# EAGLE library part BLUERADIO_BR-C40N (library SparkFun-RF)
Bluetooth SMD Module BR-C40A with antenna cut off. 50 Ohm antenna trace and connector required. Footprint fully proven. Spark Fun Electronics SKU : WRL-00149

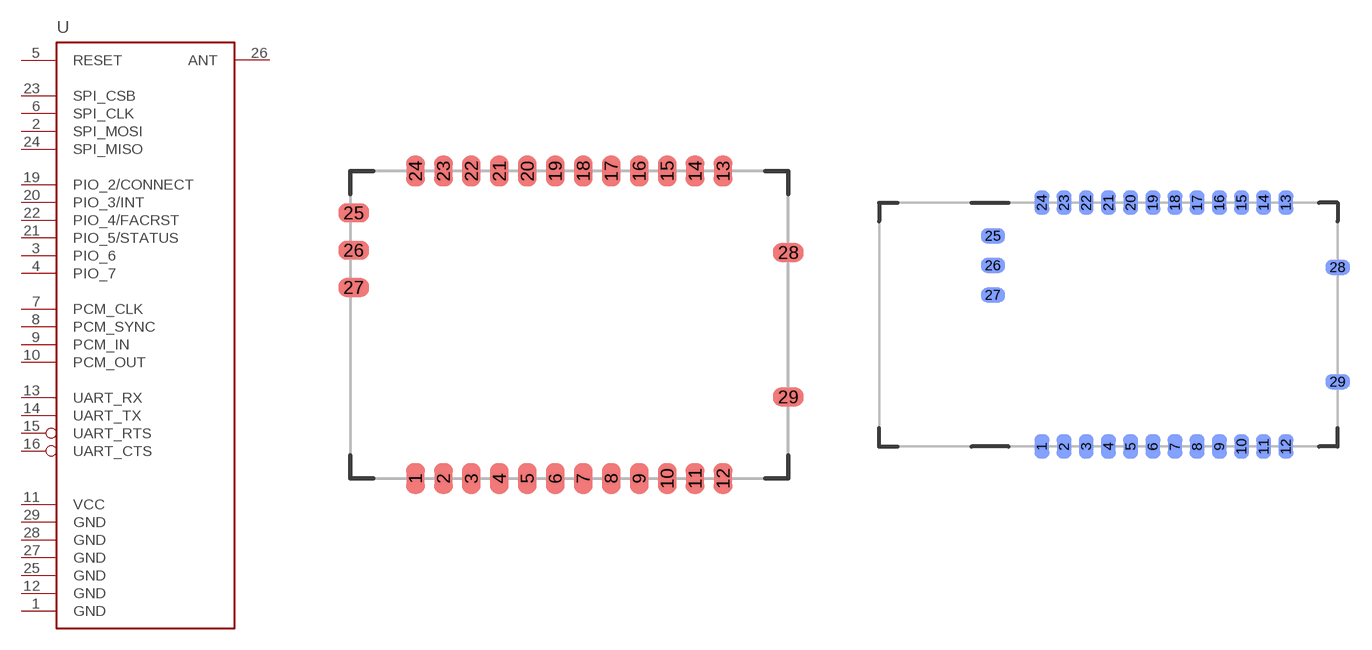
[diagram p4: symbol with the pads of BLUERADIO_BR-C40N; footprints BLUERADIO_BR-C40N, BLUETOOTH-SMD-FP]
Designator prefix -

## BLUERADIO_BR-C40NBAS  [BLUERADIO_BR-C40N]
1  GND  pwr
2  SPI_MOSI
3  PIO_6
4  PIO_7
5  RESET
6  SPI_CLK
7  PCM_CLK
8  PCM_SYNC
9  PCM_IN
10  PCM_OUT
11  VCC
12  GND  pwr
13  UART_RX  in
14  UART_TX  out
15  UART_RTS  out
16  UART_CTS  in
19  PIO_2/CONNECT  out
20  PIO_3/INT  in
21  PIO_5/STATUS  out
22  PIO_4/FACRST
23  SPI_CSB
24  SPI_MISO
25  GND  pwr
26  ANT
27  GND  pwr
28  GND  pwr
29  GND  pwr

## BLUERADIO_BR-C40NSFE  [BLUETOOTH-SMD-FP]
Pads as for BLUERADIO_BR-C40N

## BLUERADIO_BR-C40NINTERNAL  [BLUETOOTH-INTERNAL-FP]
Pads as for BLUERADIO_BR-C40N

## BLUERADIO_BR-C40NINT2  [BLUETOOTH-INTERNAL-FP2]
Pads as for BLUERADIO_BR-C40N

## Footprint BLUERADIO_BR-C40N (pad centres in mm)
smd 0.8 x 1.3: 1 -6.6,-6.6; 2 -5.4,-6.6; 3 -4.2,-6.6; 4 -3,-6.6; 5 -1.8,-6.6; 6 -0.6,-6.6; 7 0.6,-6.6; 8 1.8,-6.6; 9 3,-6.6; 10 4.2,-6.6; 11 5.4,-6.6; 12 6.6,-6.6; 13 6.6,6.6; 14 5.4,6.6; 15 4.2,6.6; 16 3,6.6; 17 1.8,6.6; 18 0.6,6.6; 19 -0.6,6.6; 20 -1.8,6.6; 21 -3,6.6; 22 -4.2,6.6; 23 -5.4,6.6; 24 -6.6,6.6
smd 1.3 x 0.8: 25 -9.25,4.8; 26 -9.25,3.2; 27 -9.25,1.6; 28 9.4,3.1; 29 9.4,-3.1

## Footprint BLUETOOTH-SMD-FP (pad centres in mm)
smd 0.8 x 1.3 bottom: 1 -6.6,-6.6; 2 -5.4,-6.6; 3 -4.2,-6.6; 4 -3,-6.6; 5 -1.8,-6.6; 6 -0.6,-6.6; 7 0.6,-6.6; 8 1.8,-6.6; 9 3,-6.6; 10 4.2,-6.6; 11 5.4,-6.6; 12 6.6,-6.6; 13 6.6,6.6; 14 5.4,6.6; 15 4.2,6.6; 16 3,6.6; 17 1.8,6.6; 18 0.6,6.6; 19 -0.6,6.6; 20 -1.8,6.6; 21 -3,6.6; 22 -4.2,6.6; 23 -5.4,6.6; 24 -6.6,6.6
smd 1.3 x 0.8 bottom: 25 -9.25,4.8; 26 -9.25,3.2; 27 -9.25,1.6; 28 9.4,3.1; 29 9.4,-3.1

## Footprint BLUETOOTH-INTERNAL-FP (pad centres in mm)
smd 0.8 x 2.25 bottom: 1 -6.6,-6.6; 2 -5.4,-6.6; 3 -4.2,-6.6; 4 -3,-6.6; 5 -1.8,-6.6; 6 -0.6,-6.6; 7 0.6,-6.6; 8 1.8,-6.6; 9 3,-6.6; 10 4.2,-6.6; 11 5.4,-6.6; 12 6.6,-6.6; 13 6.6,6.6; 14 5.4,6.6; 15 4.2,6.6; 16 3,6.6; 17 1.8,6.6; 18 0.6,6.6; 19 -0.6,6.6; 20 -1.8,6.6; 21 -3,6.6; 22 -4.2,6.6; 23 -5.4,6.6; 24 -6.6,6.6
smd 1.8 x 0.8 bottom: 25 -9.25,4.8; 26 -9.25,3.2; 27 -9.25,1.6
smd 2.25 x 0.8 bottom: 28 9.4,3.1; 29 9.4,-3.1

## Footprint BLUETOOTH-INTERNAL-FP2 (pad centres in mm)
drill 0.5 pad 0.75 long: 1 -6.6,-6.6; 2 -5.4,-6.6; 3 -4.2,-6.6; 4 -3,-6.6; 5 -1.8,-6.6; 6 -0.6,-6.6; 7 0.6,-6.6; 8 1.8,-6.6; 9 3,-6.6; 10 4.2,-6.6; 11 5.4,-6.6; 12 6.6,-6.6; 13 6.6,6.6; 14 5.4,6.6; 15 4.2,6.6; 16 3,6.6; 17 1.8,6.6; 18 0.6,6.6; 19 -0.6,6.6; 20 -1.8,6.6; 21 -3,6.6; 22 -4.2,6.6; 23 -5.4,6.6; 24 -6.6,6.6; 28 9.4,3.1; 29 9.4,-3.1
smd 1.8 x 0.8 bottom: 25 -9.25,4.8; 26 -9.25,3.2; 27 -9.25,1.6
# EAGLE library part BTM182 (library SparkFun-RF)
BTM-182 Bluetooth Module from Rayson

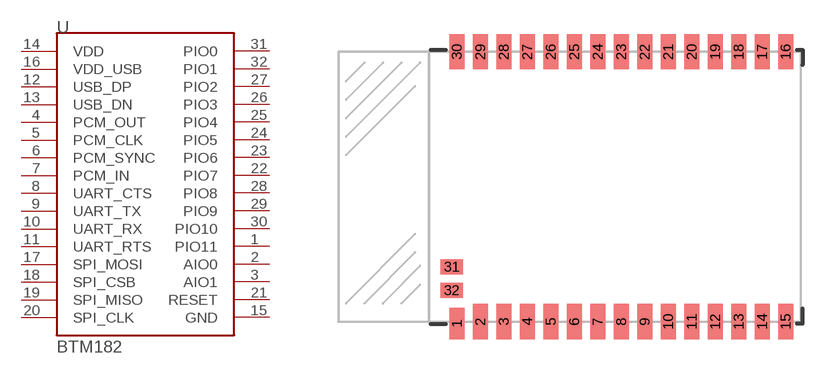
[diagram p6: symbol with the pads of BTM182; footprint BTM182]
Designator prefix U

## BTM182_  [BTM182]
1  PIO11
2  AIO0
3  AIO1
4  PCM_OUT
5  PCM_CLK
6  PCM_SYNC
7  PCM_IN
8  UART_CTS
9  UART_TX
10  UART_RX
11  UART_RTS
12  USB_DP
13  USB_DN
14  VDD
15  GND
16  VDD_USB
17  SPI_MOSI
18  SPI_CSB
19  SPI_MISO
20  SPI_CLK
21  RESET
22  PIO7
23  PIO6
24  PIO5
25  PIO4
26  PIO3
27  PIO2
28  PIO8
29  PIO9
30  PIO10
31  PIO0
32  PIO1

## Footprint BTM182 (pad centres in mm)
BTM-182 Class2 Bluetooth Module from Rayson
smd 0.8 x 1.7: 1 0,-0.1
smd 0.8 x 1.9: 2 1.27,0; 3 2.54,0; 4 3.81,0; 5 5.08,0; 6 6.35,0; 7 7.62,0; 8 8.89,0; 9 10.16,0; 10 11.43,0; 11 12.7,0; 12 13.97,0; 13 15.24,0; 14 16.51,0; 15 17.78,0; 16 17.78,14.6; 17 16.51,14.6; 18 15.24,14.6; 19 13.97,14.6; 20 12.7,14.6; 21 11.43,14.6; 22 10.16,14.6; 23 8.89,14.6; 24 7.62,14.6; 25 6.35,14.6; 26 5.08,14.6; 27 3.81,14.6; 28 2.54,14.6; 29 1.27,14.6; 30 0,14.6
smd 1.2 x 0.8: 31 -0.28,2.96; 32 -0.28,1.69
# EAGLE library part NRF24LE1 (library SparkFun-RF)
2.4GHz transceiver

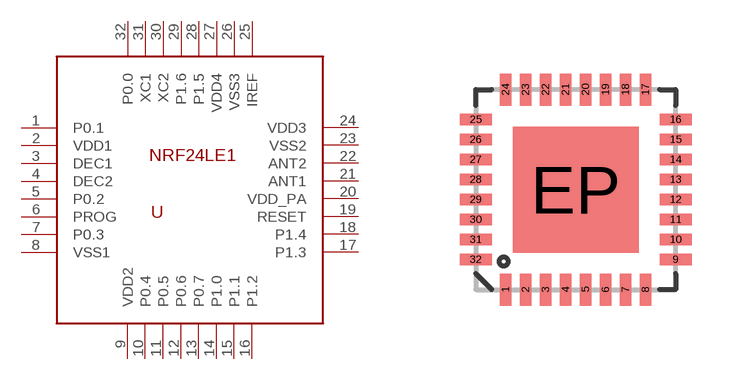
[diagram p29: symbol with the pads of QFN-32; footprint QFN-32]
Designator prefix -

## NRF24LE1  [QFN-32]
1  P0.1
2  VDD1
3  DEC1
4  DEC2
5  P0.2
6  PROG
7  P0.3
8  VSS1
9  VDD2
10  P0.4
11  P0.5
12  P0.6
13  P0.7
14  P1.0
15  P1.1
16  P1.2
17  P1.3
18  P1.4
19  RESET
20  VDD_PA
21  ANT1
22  ANT2
23  VSS2
24  VDD3
25  IREF
26  VSS3
27  VDD4
28  P1.5
29  P1.6
30  XC2
31  XC1
32  P0.0

## Footprint QFN-32 (pad centres in mm)
QFN 32-Pin package w/ Thermal Pad ***Unproven*** Applicable Parts: TLC5940
smd 0.285 x 0.8: 1 -1.75,-2.5; 2 -1.25,-2.5; 3 -0.75,-2.5; 4 -0.25,-2.5; 5 0.25,-2.5; 6 0.75,-2.5; 7 1.25,-2.5; 8 1.75,-2.5; 17 1.75,2.5; 18 1.25,2.5; 19 0.75,2.5; 20 0.25,2.5; 21 -0.25,2.5; 22 -0.75,2.5; 23 -1.25,2.5; 24 -1.75,2.5
smd 0.8 x 0.285: 9 2.5,-1.75; 10 2.5,-1.25; 11 2.5,-0.75; 12 2.5,-0.25; 13 2.5,0.25; 14 2.5,0.75; 15 2.5,1.25; 16 2.5,1.75; 25 -2.5,1.75; 26 -2.5,1.25; 27 -2.5,0.75; 28 -2.5,0.25; 29 -2.5,-0.25; 30 -2.5,-0.75; 31 -2.5,-1.25; 32 -2.5,-1.75
smd 3.15 x 3.15: EP 0,0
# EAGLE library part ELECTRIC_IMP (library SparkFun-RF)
Electric Imp SD Socket This symbol matches the Electric Imp pinout to a 4UCONN SD MMC connector. The 4UCONN part number is 19646. See this part in action on the Electric Imp Breakout.

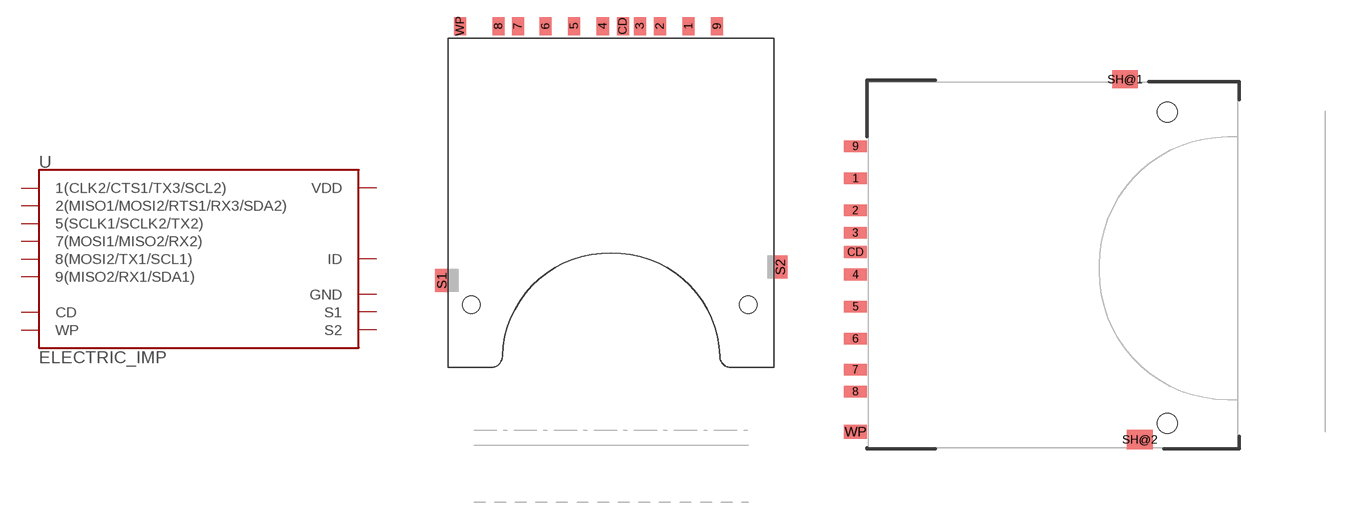
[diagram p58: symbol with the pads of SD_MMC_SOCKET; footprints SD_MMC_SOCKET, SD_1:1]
Designator prefix U

## ELECTRIC_IMPOLD (4UCONN: 19646)  [SD_MMC_SOCKET]
1  1(CLK2/CTS1/TX3/SCL2)
2  2(MISO1/MOSI2/RTS1/RX3/SDA2)
3  GND
4  VDD
5  5(SCLK1/SCLK2/TX2)
6  ID
7  7(MOSI1/MISO2/RX2)
8  8(MOSI2/TX1/SCL1)
9  9(MISO2/RX1/SDA1)
CD  CD
S1  S1
S2  S2
WP  WP

## ELECTRIC_IMP (PROD_ID: CONN-11976)  [SD_1:1]
1  1(CLK2/CTS1/TX3/SCL2)
2  2(MISO1/MOSI2/RTS1/RX3/SDA2)
3  GND
4  VDD
5  5(SCLK1/SCLK2/TX2)
6  ID
7  7(MOSI1/MISO2/RX2)
8  8(MOSI2/TX1/SCL1)
9  9(MISO2/RX1/SDA1)
CD  CD
SH@1  S1
SH@2  S2
WP  WP

## Footprint SD_MMC_SOCKET (pad centres in mm)
SD/Multi-Media Card Socket 4UCONN part # 19646
smd 1.05 x 1.56: 1 6.77,29.87; 2 4.27,29.87; 3 2.52,29.87; 4 -0.73,29.87; 5 -3.23,29.87; 6 -5.73,29.87; 7 -8.15,29.87; 8 -9.85,29.87; 9 9.27,29.87; CD 1.02,29.87; WP -13.2,29.87
smd 1.2 x 2: S1 -14.8,7.6; S2 14.8,8.8
hole 1.55 at 11.98,5.5
hole 1.55 at -12.22,5.5

## Footprint SD_1:1 (pad centres in mm)
smd 1.8 x 0.9: 1 -1,6.77; 2 -1,4.27; 3 -1,2.52; 4 -1,-0.73; 5 -1,-3.23; 6 -1,-5.73; 7 -1,-8.15; 8 -1,-9.85; 9 -1,9.27; CD -1,1.02
smd 2 x 1.4: SH@1 20,14.496
smd 2 x 1.527: SH@2 21.15,-13.589
smd 1.8 x 1.1: WP -1,-13
hole 1.55 at 23.3,11.94
hole 1.55 at 23.3,-12.32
